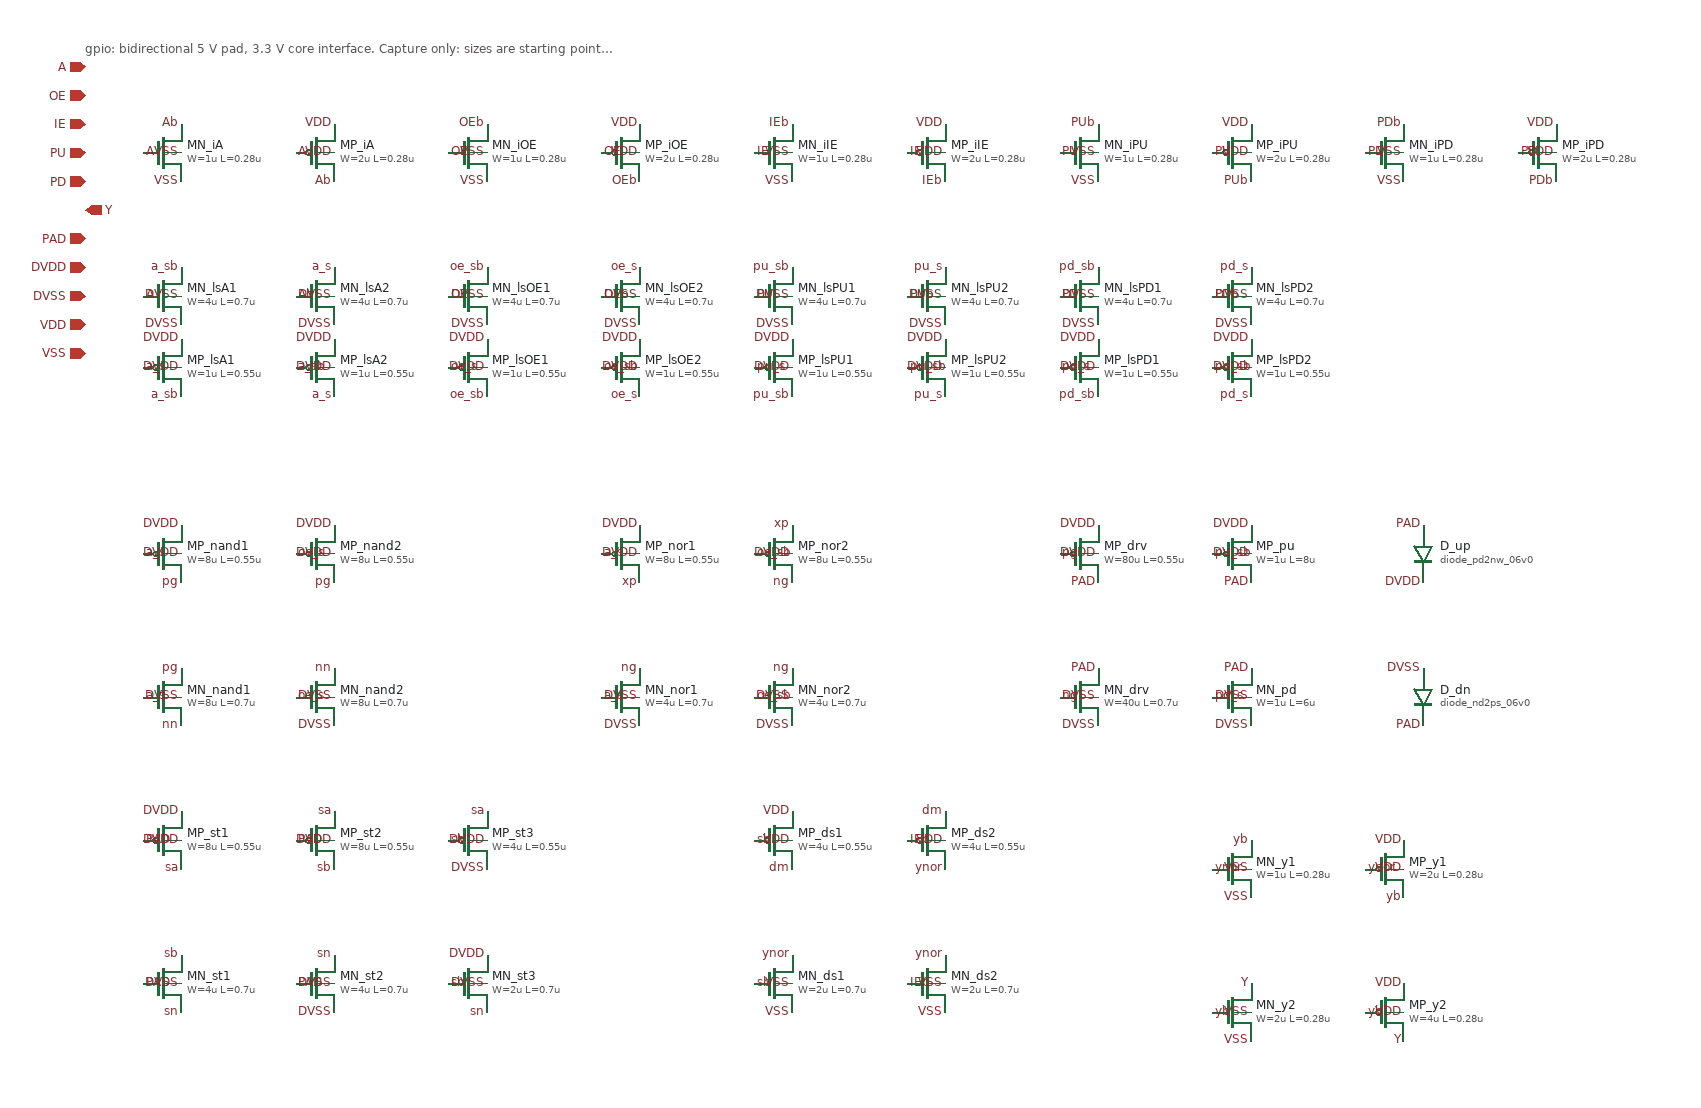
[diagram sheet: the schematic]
v {xschem version=3.4.7 file_version=1.2}
G {}
K {}
V {}
S {}
E {}
C {symbols/nfet_03v3.sym} 100 130 0 0 {name=MN_iA L=0.28u W=1u nf=1 m=1 model=nfet_03v3 spiceprefix=X}
C {devices/lab_pin.sym} 120 100 0 0 {name=l1 sig_type=std_logic lab=Ab}
C {devices/lab_pin.sym} 80 130 2 0 {name=l2 sig_type=std_logic lab=A}
C {devices/lab_pin.sym} 120 160 0 0 {name=l3 sig_type=std_logic lab=VSS}
C {devices/lab_pin.sym} 120 130 0 0 {name=l4 sig_type=std_logic lab=VSS}
C {symbols/pfet_03v3.sym} 260 130 0 0 {name=MP_iA L=0.28u W=2u nf=1 m=1 model=pfet_03v3 spiceprefix=X}
C {devices/lab_pin.sym} 280 160 0 0 {name=l5 sig_type=std_logic lab=Ab}
C {devices/lab_pin.sym} 240 130 2 0 {name=l6 sig_type=std_logic lab=A}
C {devices/lab_pin.sym} 280 100 0 0 {name=l7 sig_type=std_logic lab=VDD}
C {devices/lab_pin.sym} 280 130 0 0 {name=l8 sig_type=std_logic lab=VDD}
C {symbols/nfet_03v3.sym} 420 130 0 0 {name=MN_iOE L=0.28u W=1u nf=1 m=1 model=nfet_03v3 spiceprefix=X}
C {devices/lab_pin.sym} 440 100 0 0 {name=l9 sig_type=std_logic lab=OEb}
C {devices/lab_pin.sym} 400 130 2 0 {name=l10 sig_type=std_logic lab=OE}
C {devices/lab_pin.sym} 440 160 0 0 {name=l11 sig_type=std_logic lab=VSS}
C {devices/lab_pin.sym} 440 130 0 0 {name=l12 sig_type=std_logic lab=VSS}
C {symbols/pfet_03v3.sym} 580 130 0 0 {name=MP_iOE L=0.28u W=2u nf=1 m=1 model=pfet_03v3 spiceprefix=X}
C {devices/lab_pin.sym} 600 160 0 0 {name=l13 sig_type=std_logic lab=OEb}
C {devices/lab_pin.sym} 560 130 2 0 {name=l14 sig_type=std_logic lab=OE}
C {devices/lab_pin.sym} 600 100 0 0 {name=l15 sig_type=std_logic lab=VDD}
C {devices/lab_pin.sym} 600 130 0 0 {name=l16 sig_type=std_logic lab=VDD}
C {symbols/nfet_03v3.sym} 740 130 0 0 {name=MN_iIE L=0.28u W=1u nf=1 m=1 model=nfet_03v3 spiceprefix=X}
C {devices/lab_pin.sym} 760 100 0 0 {name=l17 sig_type=std_logic lab=IEb}
C {devices/lab_pin.sym} 720 130 2 0 {name=l18 sig_type=std_logic lab=IE}
C {devices/lab_pin.sym} 760 160 0 0 {name=l19 sig_type=std_logic lab=VSS}
C {devices/lab_pin.sym} 760 130 0 0 {name=l20 sig_type=std_logic lab=VSS}
C {symbols/pfet_03v3.sym} 900 130 0 0 {name=MP_iIE L=0.28u W=2u nf=1 m=1 model=pfet_03v3 spiceprefix=X}
C {devices/lab_pin.sym} 920 160 0 0 {name=l21 sig_type=std_logic lab=IEb}
C {devices/lab_pin.sym} 880 130 2 0 {name=l22 sig_type=std_logic lab=IE}
C {devices/lab_pin.sym} 920 100 0 0 {name=l23 sig_type=std_logic lab=VDD}
C {devices/lab_pin.sym} 920 130 0 0 {name=l24 sig_type=std_logic lab=VDD}
C {symbols/nfet_03v3.sym} 1060 130 0 0 {name=MN_iPU L=0.28u W=1u nf=1 m=1 model=nfet_03v3 spiceprefix=X}
C {devices/lab_pin.sym} 1080 100 0 0 {name=l25 sig_type=std_logic lab=PUb}
C {devices/lab_pin.sym} 1040 130 2 0 {name=l26 sig_type=std_logic lab=PU}
C {devices/lab_pin.sym} 1080 160 0 0 {name=l27 sig_type=std_logic lab=VSS}
C {devices/lab_pin.sym} 1080 130 0 0 {name=l28 sig_type=std_logic lab=VSS}
C {symbols/pfet_03v3.sym} 1220 130 0 0 {name=MP_iPU L=0.28u W=2u nf=1 m=1 model=pfet_03v3 spiceprefix=X}
C {devices/lab_pin.sym} 1240 160 0 0 {name=l29 sig_type=std_logic lab=PUb}
C {devices/lab_pin.sym} 1200 130 2 0 {name=l30 sig_type=std_logic lab=PU}
C {devices/lab_pin.sym} 1240 100 0 0 {name=l31 sig_type=std_logic lab=VDD}
C {devices/lab_pin.sym} 1240 130 0 0 {name=l32 sig_type=std_logic lab=VDD}
C {symbols/nfet_03v3.sym} 1380 130 0 0 {name=MN_iPD L=0.28u W=1u nf=1 m=1 model=nfet_03v3 spiceprefix=X}
C {devices/lab_pin.sym} 1400 100 0 0 {name=l33 sig_type=std_logic lab=PDb}
C {devices/lab_pin.sym} 1360 130 2 0 {name=l34 sig_type=std_logic lab=PD}
C {devices/lab_pin.sym} 1400 160 0 0 {name=l35 sig_type=std_logic lab=VSS}
C {devices/lab_pin.sym} 1400 130 0 0 {name=l36 sig_type=std_logic lab=VSS}
C {symbols/pfet_03v3.sym} 1540 130 0 0 {name=MP_iPD L=0.28u W=2u nf=1 m=1 model=pfet_03v3 spiceprefix=X}
C {devices/lab_pin.sym} 1560 160 0 0 {name=l37 sig_type=std_logic lab=PDb}
C {devices/lab_pin.sym} 1520 130 2 0 {name=l38 sig_type=std_logic lab=PD}
C {devices/lab_pin.sym} 1560 100 0 0 {name=l39 sig_type=std_logic lab=VDD}
C {devices/lab_pin.sym} 1560 130 0 0 {name=l40 sig_type=std_logic lab=VDD}
C {symbols/nfet_06v0.sym} 100 280 0 0 {name=MN_lsA1 L=0.7u W=4u nf=1 m=1 model=nfet_06v0 spiceprefix=X}
C {devices/lab_pin.sym} 120 250 0 0 {name=l41 sig_type=std_logic lab=a_sb}
C {devices/lab_pin.sym} 80 280 2 0 {name=l42 sig_type=std_logic lab=A}
C {devices/lab_pin.sym} 120 310 0 0 {name=l43 sig_type=std_logic lab=DVSS}
C {devices/lab_pin.sym} 120 280 0 0 {name=l44 sig_type=std_logic lab=DVSS}
C {symbols/nfet_06v0.sym} 260 280 0 0 {name=MN_lsA2 L=0.7u W=4u nf=1 m=1 model=nfet_06v0 spiceprefix=X}
C {devices/lab_pin.sym} 280 250 0 0 {name=l45 sig_type=std_logic lab=a_s}
C {devices/lab_pin.sym} 240 280 2 0 {name=l46 sig_type=std_logic lab=Ab}
C {devices/lab_pin.sym} 280 310 0 0 {name=l47 sig_type=std_logic lab=DVSS}
C {devices/lab_pin.sym} 280 280 0 0 {name=l48 sig_type=std_logic lab=DVSS}
C {symbols/pfet_06v0.sym} 100 355 0 0 {name=MP_lsA1 L=0.55u W=1u nf=1 m=1 model=pfet_06v0 spiceprefix=X}
C {devices/lab_pin.sym} 120 385 0 0 {name=l49 sig_type=std_logic lab=a_sb}
C {devices/lab_pin.sym} 80 355 2 0 {name=l50 sig_type=std_logic lab=a_s}
C {devices/lab_pin.sym} 120 325 0 0 {name=l51 sig_type=std_logic lab=DVDD}
C {devices/lab_pin.sym} 120 355 0 0 {name=l52 sig_type=std_logic lab=DVDD}
C {symbols/pfet_06v0.sym} 260 355 0 0 {name=MP_lsA2 L=0.55u W=1u nf=1 m=1 model=pfet_06v0 spiceprefix=X}
C {devices/lab_pin.sym} 280 385 0 0 {name=l53 sig_type=std_logic lab=a_s}
C {devices/lab_pin.sym} 240 355 2 0 {name=l54 sig_type=std_logic lab=a_sb}
C {devices/lab_pin.sym} 280 325 0 0 {name=l55 sig_type=std_logic lab=DVDD}
C {devices/lab_pin.sym} 280 355 0 0 {name=l56 sig_type=std_logic lab=DVDD}
C {symbols/nfet_06v0.sym} 420 280 0 0 {name=MN_lsOE1 L=0.7u W=4u nf=1 m=1 model=nfet_06v0 spiceprefix=X}
C {devices/lab_pin.sym} 440 250 0 0 {name=l57 sig_type=std_logic lab=oe_sb}
C {devices/lab_pin.sym} 400 280 2 0 {name=l58 sig_type=std_logic lab=OE}
C {devices/lab_pin.sym} 440 310 0 0 {name=l59 sig_type=std_logic lab=DVSS}
C {devices/lab_pin.sym} 440 280 0 0 {name=l60 sig_type=std_logic lab=DVSS}
C {symbols/nfet_06v0.sym} 580 280 0 0 {name=MN_lsOE2 L=0.7u W=4u nf=1 m=1 model=nfet_06v0 spiceprefix=X}
C {devices/lab_pin.sym} 600 250 0 0 {name=l61 sig_type=std_logic lab=oe_s}
C {devices/lab_pin.sym} 560 280 2 0 {name=l62 sig_type=std_logic lab=OEb}
C {devices/lab_pin.sym} 600 310 0 0 {name=l63 sig_type=std_logic lab=DVSS}
C {devices/lab_pin.sym} 600 280 0 0 {name=l64 sig_type=std_logic lab=DVSS}
C {symbols/pfet_06v0.sym} 420 355 0 0 {name=MP_lsOE1 L=0.55u W=1u nf=1 m=1 model=pfet_06v0 spiceprefix=X}
C {devices/lab_pin.sym} 440 385 0 0 {name=l65 sig_type=std_logic lab=oe_sb}
C {devices/lab_pin.sym} 400 355 2 0 {name=l66 sig_type=std_logic lab=oe_s}
C {devices/lab_pin.sym} 440 325 0 0 {name=l67 sig_type=std_logic lab=DVDD}
C {devices/lab_pin.sym} 440 355 0 0 {name=l68 sig_type=std_logic lab=DVDD}
C {symbols/pfet_06v0.sym} 580 355 0 0 {name=MP_lsOE2 L=0.55u W=1u nf=1 m=1 model=pfet_06v0 spiceprefix=X}
C {devices/lab_pin.sym} 600 385 0 0 {name=l69 sig_type=std_logic lab=oe_s}
C {devices/lab_pin.sym} 560 355 2 0 {name=l70 sig_type=std_logic lab=oe_sb}
C {devices/lab_pin.sym} 600 325 0 0 {name=l71 sig_type=std_logic lab=DVDD}
C {devices/lab_pin.sym} 600 355 0 0 {name=l72 sig_type=std_logic lab=DVDD}
C {symbols/nfet_06v0.sym} 740 280 0 0 {name=MN_lsPU1 L=0.7u W=4u nf=1 m=1 model=nfet_06v0 spiceprefix=X}
C {devices/lab_pin.sym} 760 250 0 0 {name=l73 sig_type=std_logic lab=pu_sb}
C {devices/lab_pin.sym} 720 280 2 0 {name=l74 sig_type=std_logic lab=PU}
C {devices/lab_pin.sym} 760 310 0 0 {name=l75 sig_type=std_logic lab=DVSS}
C {devices/lab_pin.sym} 760 280 0 0 {name=l76 sig_type=std_logic lab=DVSS}
C {symbols/nfet_06v0.sym} 900 280 0 0 {name=MN_lsPU2 L=0.7u W=4u nf=1 m=1 model=nfet_06v0 spiceprefix=X}
C {devices/lab_pin.sym} 920 250 0 0 {name=l77 sig_type=std_logic lab=pu_s}
C {devices/lab_pin.sym} 880 280 2 0 {name=l78 sig_type=std_logic lab=PUb}
C {devices/lab_pin.sym} 920 310 0 0 {name=l79 sig_type=std_logic lab=DVSS}
C {devices/lab_pin.sym} 920 280 0 0 {name=l80 sig_type=std_logic lab=DVSS}
C {symbols/pfet_06v0.sym} 740 355 0 0 {name=MP_lsPU1 L=0.55u W=1u nf=1 m=1 model=pfet_06v0 spiceprefix=X}
C {devices/lab_pin.sym} 760 385 0 0 {name=l81 sig_type=std_logic lab=pu_sb}
C {devices/lab_pin.sym} 720 355 2 0 {name=l82 sig_type=std_logic lab=pu_s}
C {devices/lab_pin.sym} 760 325 0 0 {name=l83 sig_type=std_logic lab=DVDD}
C {devices/lab_pin.sym} 760 355 0 0 {name=l84 sig_type=std_logic lab=DVDD}
C {symbols/pfet_06v0.sym} 900 355 0 0 {name=MP_lsPU2 L=0.55u W=1u nf=1 m=1 model=pfet_06v0 spiceprefix=X}
C {devices/lab_pin.sym} 920 385 0 0 {name=l85 sig_type=std_logic lab=pu_s}
C {devices/lab_pin.sym} 880 355 2 0 {name=l86 sig_type=std_logic lab=pu_sb}
C {devices/lab_pin.sym} 920 325 0 0 {name=l87 sig_type=std_logic lab=DVDD}
C {devices/lab_pin.sym} 920 355 0 0 {name=l88 sig_type=std_logic lab=DVDD}
C {symbols/nfet_06v0.sym} 1060 280 0 0 {name=MN_lsPD1 L=0.7u W=4u nf=1 m=1 model=nfet_06v0 spiceprefix=X}
C {devices/lab_pin.sym} 1080 250 0 0 {name=l89 sig_type=std_logic lab=pd_sb}
C {devices/lab_pin.sym} 1040 280 2 0 {name=l90 sig_type=std_logic lab=PD}
C {devices/lab_pin.sym} 1080 310 0 0 {name=l91 sig_type=std_logic lab=DVSS}
C {devices/lab_pin.sym} 1080 280 0 0 {name=l92 sig_type=std_logic lab=DVSS}
C {symbols/nfet_06v0.sym} 1220 280 0 0 {name=MN_lsPD2 L=0.7u W=4u nf=1 m=1 model=nfet_06v0 spiceprefix=X}
C {devices/lab_pin.sym} 1240 250 0 0 {name=l93 sig_type=std_logic lab=pd_s}
C {devices/lab_pin.sym} 1200 280 2 0 {name=l94 sig_type=std_logic lab=PDb}
C {devices/lab_pin.sym} 1240 310 0 0 {name=l95 sig_type=std_logic lab=DVSS}
C {devices/lab_pin.sym} 1240 280 0 0 {name=l96 sig_type=std_logic lab=DVSS}
C {symbols/pfet_06v0.sym} 1060 355 0 0 {name=MP_lsPD1 L=0.55u W=1u nf=1 m=1 model=pfet_06v0 spiceprefix=X}
C {devices/lab_pin.sym} 1080 385 0 0 {name=l97 sig_type=std_logic lab=pd_sb}
C {devices/lab_pin.sym} 1040 355 2 0 {name=l98 sig_type=std_logic lab=pd_s}
C {devices/lab_pin.sym} 1080 325 0 0 {name=l99 sig_type=std_logic lab=DVDD}
C {devices/lab_pin.sym} 1080 355 0 0 {name=l100 sig_type=std_logic lab=DVDD}
C {symbols/pfet_06v0.sym} 1220 355 0 0 {name=MP_lsPD2 L=0.55u W=1u nf=1 m=1 model=pfet_06v0 spiceprefix=X}
C {devices/lab_pin.sym} 1240 385 0 0 {name=l101 sig_type=std_logic lab=pd_s}
C {devices/lab_pin.sym} 1200 355 2 0 {name=l102 sig_type=std_logic lab=pd_sb}
C {devices/lab_pin.sym} 1240 325 0 0 {name=l103 sig_type=std_logic lab=DVDD}
C {devices/lab_pin.sym} 1240 355 0 0 {name=l104 sig_type=std_logic lab=DVDD}
C {symbols/pfet_06v0.sym} 100 550 0 0 {name=MP_nand1 L=0.55u W=8u nf=1 m=1 model=pfet_06v0 spiceprefix=X}
C {devices/lab_pin.sym} 120 580 0 0 {name=l105 sig_type=std_logic lab=pg}
C {devices/lab_pin.sym} 80 550 2 0 {name=l106 sig_type=std_logic lab=a_s}
C {devices/lab_pin.sym} 120 520 0 0 {name=l107 sig_type=std_logic lab=DVDD}
C {devices/lab_pin.sym} 120 550 0 0 {name=l108 sig_type=std_logic lab=DVDD}
C {symbols/pfet_06v0.sym} 260 550 0 0 {name=MP_nand2 L=0.55u W=8u nf=1 m=1 model=pfet_06v0 spiceprefix=X}
C {devices/lab_pin.sym} 280 580 0 0 {name=l109 sig_type=std_logic lab=pg}
C {devices/lab_pin.sym} 240 550 2 0 {name=l110 sig_type=std_logic lab=oe_s}
C {devices/lab_pin.sym} 280 520 0 0 {name=l111 sig_type=std_logic lab=DVDD}
C {devices/lab_pin.sym} 280 550 0 0 {name=l112 sig_type=std_logic lab=DVDD}
C {symbols/nfet_06v0.sym} 100 700 0 0 {name=MN_nand1 L=0.7u W=8u nf=1 m=1 model=nfet_06v0 spiceprefix=X}
C {devices/lab_pin.sym} 120 670 0 0 {name=l113 sig_type=std_logic lab=pg}
C {devices/lab_pin.sym} 80 700 2 0 {name=l114 sig_type=std_logic lab=a_s}
C {devices/lab_pin.sym} 120 730 0 0 {name=l115 sig_type=std_logic lab=nn}
C {devices/lab_pin.sym} 120 700 0 0 {name=l116 sig_type=std_logic lab=DVSS}
C {symbols/nfet_06v0.sym} 260 700 0 0 {name=MN_nand2 L=0.7u W=8u nf=1 m=1 model=nfet_06v0 spiceprefix=X}
C {devices/lab_pin.sym} 280 670 0 0 {name=l117 sig_type=std_logic lab=nn}
C {devices/lab_pin.sym} 240 700 2 0 {name=l118 sig_type=std_logic lab=oe_s}
C {devices/lab_pin.sym} 280 730 0 0 {name=l119 sig_type=std_logic lab=DVSS}
C {devices/lab_pin.sym} 280 700 0 0 {name=l120 sig_type=std_logic lab=DVSS}
C {symbols/pfet_06v0.sym} 580 550 0 0 {name=MP_nor1 L=0.55u W=8u nf=1 m=1 model=pfet_06v0 spiceprefix=X}
C {devices/lab_pin.sym} 600 580 0 0 {name=l121 sig_type=std_logic lab=xp}
C {devices/lab_pin.sym} 560 550 2 0 {name=l122 sig_type=std_logic lab=a_s}
C {devices/lab_pin.sym} 600 520 0 0 {name=l123 sig_type=std_logic lab=DVDD}
C {devices/lab_pin.sym} 600 550 0 0 {name=l124 sig_type=std_logic lab=DVDD}
C {symbols/pfet_06v0.sym} 740 550 0 0 {name=MP_nor2 L=0.55u W=8u nf=1 m=1 model=pfet_06v0 spiceprefix=X}
C {devices/lab_pin.sym} 760 580 0 0 {name=l125 sig_type=std_logic lab=ng}
C {devices/lab_pin.sym} 720 550 2 0 {name=l126 sig_type=std_logic lab=oe_sb}
C {devices/lab_pin.sym} 760 520 0 0 {name=l127 sig_type=std_logic lab=xp}
C {devices/lab_pin.sym} 760 550 0 0 {name=l128 sig_type=std_logic lab=DVDD}
C {symbols/nfet_06v0.sym} 580 700 0 0 {name=MN_nor1 L=0.7u W=4u nf=1 m=1 model=nfet_06v0 spiceprefix=X}
C {devices/lab_pin.sym} 600 670 0 0 {name=l129 sig_type=std_logic lab=ng}
C {devices/lab_pin.sym} 560 700 2 0 {name=l130 sig_type=std_logic lab=a_s}
C {devices/lab_pin.sym} 600 730 0 0 {name=l131 sig_type=std_logic lab=DVSS}
C {devices/lab_pin.sym} 600 700 0 0 {name=l132 sig_type=std_logic lab=DVSS}
C {symbols/nfet_06v0.sym} 740 700 0 0 {name=MN_nor2 L=0.7u W=4u nf=1 m=1 model=nfet_06v0 spiceprefix=X}
C {devices/lab_pin.sym} 760 670 0 0 {name=l133 sig_type=std_logic lab=ng}
C {devices/lab_pin.sym} 720 700 2 0 {name=l134 sig_type=std_logic lab=oe_sb}
C {devices/lab_pin.sym} 760 730 0 0 {name=l135 sig_type=std_logic lab=DVSS}
C {devices/lab_pin.sym} 760 700 0 0 {name=l136 sig_type=std_logic lab=DVSS}
C {symbols/pfet_06v0.sym} 1060 550 0 0 {name=MP_drv L=0.55u W=80u nf=16 m=1 model=pfet_06v0 spiceprefix=X}
C {devices/lab_pin.sym} 1080 580 0 0 {name=l137 sig_type=std_logic lab=PAD}
C {devices/lab_pin.sym} 1040 550 2 0 {name=l138 sig_type=std_logic lab=pg}
C {devices/lab_pin.sym} 1080 520 0 0 {name=l139 sig_type=std_logic lab=DVDD}
C {devices/lab_pin.sym} 1080 550 0 0 {name=l140 sig_type=std_logic lab=DVDD}
C {symbols/nfet_06v0.sym} 1060 700 0 0 {name=MN_drv L=0.7u W=40u nf=8 m=1 model=nfet_06v0 spiceprefix=X}
C {devices/lab_pin.sym} 1080 670 0 0 {name=l141 sig_type=std_logic lab=PAD}
C {devices/lab_pin.sym} 1040 700 2 0 {name=l142 sig_type=std_logic lab=ng}
C {devices/lab_pin.sym} 1080 730 0 0 {name=l143 sig_type=std_logic lab=DVSS}
C {devices/lab_pin.sym} 1080 700 0 0 {name=l144 sig_type=std_logic lab=DVSS}
C {symbols/pfet_06v0.sym} 1220 550 0 0 {name=MP_pu L=8u W=1u nf=1 m=1 model=pfet_06v0 spiceprefix=X}
C {devices/lab_pin.sym} 1240 580 0 0 {name=l145 sig_type=std_logic lab=PAD}
C {devices/lab_pin.sym} 1200 550 2 0 {name=l146 sig_type=std_logic lab=pu_sb}
C {devices/lab_pin.sym} 1240 520 0 0 {name=l147 sig_type=std_logic lab=DVDD}
C {devices/lab_pin.sym} 1240 550 0 0 {name=l148 sig_type=std_logic lab=DVDD}
C {symbols/nfet_06v0.sym} 1220 700 0 0 {name=MN_pd L=6u W=1u nf=1 m=1 model=nfet_06v0 spiceprefix=X}
C {devices/lab_pin.sym} 1240 670 0 0 {name=l149 sig_type=std_logic lab=PAD}
C {devices/lab_pin.sym} 1200 700 2 0 {name=l150 sig_type=std_logic lab=pd_s}
C {devices/lab_pin.sym} 1240 730 0 0 {name=l151 sig_type=std_logic lab=DVSS}
C {devices/lab_pin.sym} 1240 700 0 0 {name=l152 sig_type=std_logic lab=DVSS}
C {symbols/diode_pd2nw_06v0.sym} 1420 550 0 0 {name=D_up model=diode_pd2nw_06v0 r_w=10u r_l=17.8u m=1}
C {devices/lab_pin.sym} 1420 520 3 0 {name=l153 sig_type=std_logic lab=PAD}
C {devices/lab_pin.sym} 1420 580 1 0 {name=l154 sig_type=std_logic lab=DVDD}
C {symbols/diode_nd2ps_06v0.sym} 1420 700 0 0 {name=D_dn model=diode_nd2ps_06v0 r_w=10u r_l=17.8u m=1}
C {devices/lab_pin.sym} 1420 670 3 0 {name=l155 sig_type=std_logic lab=DVSS}
C {devices/lab_pin.sym} 1420 730 1 0 {name=l156 sig_type=std_logic lab=PAD}
C {symbols/pfet_06v0.sym} 100 850 0 0 {name=MP_st1 L=0.55u W=8u nf=1 m=1 model=pfet_06v0 spiceprefix=X}
C {devices/lab_pin.sym} 120 880 0 0 {name=l157 sig_type=std_logic lab=sa}
C {devices/lab_pin.sym} 80 850 2 0 {name=l158 sig_type=std_logic lab=PAD}
C {devices/lab_pin.sym} 120 820 0 0 {name=l159 sig_type=std_logic lab=DVDD}
C {devices/lab_pin.sym} 120 850 0 0 {name=l160 sig_type=std_logic lab=DVDD}
C {symbols/pfet_06v0.sym} 260 850 0 0 {name=MP_st2 L=0.55u W=8u nf=1 m=1 model=pfet_06v0 spiceprefix=X}
C {devices/lab_pin.sym} 280 880 0 0 {name=l161 sig_type=std_logic lab=sb}
C {devices/lab_pin.sym} 240 850 2 0 {name=l162 sig_type=std_logic lab=PAD}
C {devices/lab_pin.sym} 280 820 0 0 {name=l163 sig_type=std_logic lab=sa}
C {devices/lab_pin.sym} 280 850 0 0 {name=l164 sig_type=std_logic lab=DVDD}
C {symbols/pfet_06v0.sym} 420 850 0 0 {name=MP_st3 L=0.55u W=4u nf=1 m=1 model=pfet_06v0 spiceprefix=X}
C {devices/lab_pin.sym} 440 880 0 0 {name=l165 sig_type=std_logic lab=DVSS}
C {devices/lab_pin.sym} 400 850 2 0 {name=l166 sig_type=std_logic lab=sb}
C {devices/lab_pin.sym} 440 820 0 0 {name=l167 sig_type=std_logic lab=sa}
C {devices/lab_pin.sym} 440 850 0 0 {name=l168 sig_type=std_logic lab=DVDD}
C {symbols/nfet_06v0.sym} 100 1000 0 0 {name=MN_st1 L=0.7u W=4u nf=1 m=1 model=nfet_06v0 spiceprefix=X}
C {devices/lab_pin.sym} 120 970 0 0 {name=l169 sig_type=std_logic lab=sb}
C {devices/lab_pin.sym} 80 1000 2 0 {name=l170 sig_type=std_logic lab=PAD}
C {devices/lab_pin.sym} 120 1030 0 0 {name=l171 sig_type=std_logic lab=sn}
C {devices/lab_pin.sym} 120 1000 0 0 {name=l172 sig_type=std_logic lab=DVSS}
C {symbols/nfet_06v0.sym} 260 1000 0 0 {name=MN_st2 L=0.7u W=4u nf=1 m=1 model=nfet_06v0 spiceprefix=X}
C {devices/lab_pin.sym} 280 970 0 0 {name=l173 sig_type=std_logic lab=sn}
C {devices/lab_pin.sym} 240 1000 2 0 {name=l174 sig_type=std_logic lab=PAD}
C {devices/lab_pin.sym} 280 1030 0 0 {name=l175 sig_type=std_logic lab=DVSS}
C {devices/lab_pin.sym} 280 1000 0 0 {name=l176 sig_type=std_logic lab=DVSS}
C {symbols/nfet_06v0.sym} 420 1000 0 0 {name=MN_st3 L=0.7u W=2u nf=1 m=1 model=nfet_06v0 spiceprefix=X}
C {devices/lab_pin.sym} 440 970 0 0 {name=l177 sig_type=std_logic lab=DVDD}
C {devices/lab_pin.sym} 400 1000 2 0 {name=l178 sig_type=std_logic lab=sb}
C {devices/lab_pin.sym} 440 1030 0 0 {name=l179 sig_type=std_logic lab=sn}
C {devices/lab_pin.sym} 440 1000 0 0 {name=l180 sig_type=std_logic lab=DVSS}
C {symbols/pfet_06v0.sym} 740 850 0 0 {name=MP_ds1 L=0.55u W=4u nf=1 m=1 model=pfet_06v0 spiceprefix=X}
C {devices/lab_pin.sym} 760 880 0 0 {name=l181 sig_type=std_logic lab=dm}
C {devices/lab_pin.sym} 720 850 2 0 {name=l182 sig_type=std_logic lab=sb}
C {devices/lab_pin.sym} 760 820 0 0 {name=l183 sig_type=std_logic lab=VDD}
C {devices/lab_pin.sym} 760 850 0 0 {name=l184 sig_type=std_logic lab=VDD}
C {symbols/pfet_06v0.sym} 900 850 0 0 {name=MP_ds2 L=0.55u W=4u nf=1 m=1 model=pfet_06v0 spiceprefix=X}
C {devices/lab_pin.sym} 920 880 0 0 {name=l185 sig_type=std_logic lab=ynor}
C {devices/lab_pin.sym} 880 850 2 0 {name=l186 sig_type=std_logic lab=IEb}
C {devices/lab_pin.sym} 920 820 0 0 {name=l187 sig_type=std_logic lab=dm}
C {devices/lab_pin.sym} 920 850 0 0 {name=l188 sig_type=std_logic lab=VDD}
C {symbols/nfet_06v0.sym} 740 1000 0 0 {name=MN_ds1 L=0.7u W=2u nf=1 m=1 model=nfet_06v0 spiceprefix=X}
C {devices/lab_pin.sym} 760 970 0 0 {name=l189 sig_type=std_logic lab=ynor}
C {devices/lab_pin.sym} 720 1000 2 0 {name=l190 sig_type=std_logic lab=sb}
C {devices/lab_pin.sym} 760 1030 0 0 {name=l191 sig_type=std_logic lab=VSS}
C {devices/lab_pin.sym} 760 1000 0 0 {name=l192 sig_type=std_logic lab=VSS}
C {symbols/nfet_06v0.sym} 900 1000 0 0 {name=MN_ds2 L=0.7u W=2u nf=1 m=1 model=nfet_06v0 spiceprefix=X}
C {devices/lab_pin.sym} 920 970 0 0 {name=l193 sig_type=std_logic lab=ynor}
C {devices/lab_pin.sym} 880 1000 2 0 {name=l194 sig_type=std_logic lab=IEb}
C {devices/lab_pin.sym} 920 1030 0 0 {name=l195 sig_type=std_logic lab=VSS}
C {devices/lab_pin.sym} 920 1000 0 0 {name=l196 sig_type=std_logic lab=VSS}
C {symbols/nfet_03v3.sym} 1220 880 0 0 {name=MN_y1 L=0.28u W=1u nf=1 m=1 model=nfet_03v3 spiceprefix=X}
C {devices/lab_pin.sym} 1240 850 0 0 {name=l197 sig_type=std_logic lab=yb}
C {devices/lab_pin.sym} 1200 880 2 0 {name=l198 sig_type=std_logic lab=ynor}
C {devices/lab_pin.sym} 1240 910 0 0 {name=l199 sig_type=std_logic lab=VSS}
C {devices/lab_pin.sym} 1240 880 0 0 {name=l200 sig_type=std_logic lab=VSS}
C {symbols/pfet_03v3.sym} 1380 880 0 0 {name=MP_y1 L=0.28u W=2u nf=1 m=1 model=pfet_03v3 spiceprefix=X}
C {devices/lab_pin.sym} 1400 910 0 0 {name=l201 sig_type=std_logic lab=yb}
C {devices/lab_pin.sym} 1360 880 2 0 {name=l202 sig_type=std_logic lab=ynor}
C {devices/lab_pin.sym} 1400 850 0 0 {name=l203 sig_type=std_logic lab=VDD}
C {devices/lab_pin.sym} 1400 880 0 0 {name=l204 sig_type=std_logic lab=VDD}
C {symbols/nfet_03v3.sym} 1220 1030 0 0 {name=MN_y2 L=0.28u W=2u nf=1 m=1 model=nfet_03v3 spiceprefix=X}
C {devices/lab_pin.sym} 1240 1000 0 0 {name=l205 sig_type=std_logic lab=Y}
C {devices/lab_pin.sym} 1200 1030 2 0 {name=l206 sig_type=std_logic lab=yb}
C {devices/lab_pin.sym} 1240 1060 0 0 {name=l207 sig_type=std_logic lab=VSS}
C {devices/lab_pin.sym} 1240 1030 0 0 {name=l208 sig_type=std_logic lab=VSS}
C {symbols/pfet_03v3.sym} 1380 1030 0 0 {name=MP_y2 L=0.28u W=4u nf=1 m=1 model=pfet_03v3 spiceprefix=X}
C {devices/lab_pin.sym} 1400 1060 0 0 {name=l209 sig_type=std_logic lab=Y}
C {devices/lab_pin.sym} 1360 1030 2 0 {name=l210 sig_type=std_logic lab=yb}
C {devices/lab_pin.sym} 1400 1000 0 0 {name=l211 sig_type=std_logic lab=VDD}
C {devices/lab_pin.sym} 1400 1030 0 0 {name=l212 sig_type=std_logic lab=VDD}
C {devices/ipin.sym} 20 40 0 0 {name=p213 lab=A}
C {devices/ipin.sym} 20 70 0 0 {name=p214 lab=OE}
C {devices/ipin.sym} 20 100 0 0 {name=p215 lab=IE}
C {devices/ipin.sym} 20 130 0 0 {name=p216 lab=PU}
C {devices/ipin.sym} 20 160 0 0 {name=p217 lab=PD}
C {devices/opin.sym} 20 190 0 0 {name=p218 lab=Y}
C {devices/iopin.sym} 20 220 0 0 {name=p219 lab=PAD}
C {devices/iopin.sym} 20 250 0 0 {name=p220 lab=DVDD}
C {devices/iopin.sym} 20 280 0 0 {name=p221 lab=DVSS}
C {devices/iopin.sym} 20 310 0 0 {name=p222 lab=VDD}
C {devices/iopin.sym} 20 340 0 0 {name=p223 lab=VSS}
T {gpio: bidirectional 5 V pad, 3.3 V core interface. Capture only: sizes are starting points, verified in later issues.} 20 10 0 0 0.4 0.4 {}
